One B-rep face of a CAD part: STEP entity #1117.
In plain terms, the planar face has unit normal (1, 0, 0).
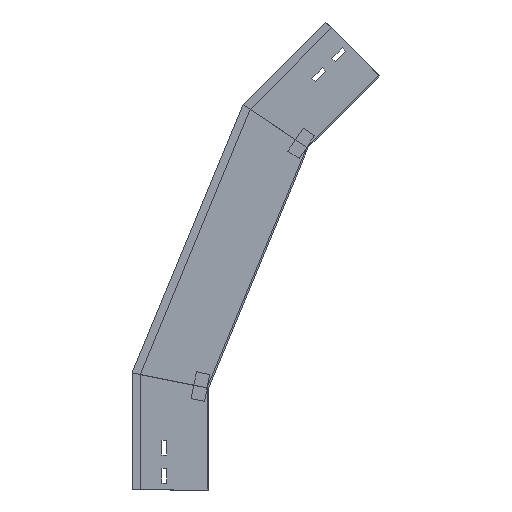
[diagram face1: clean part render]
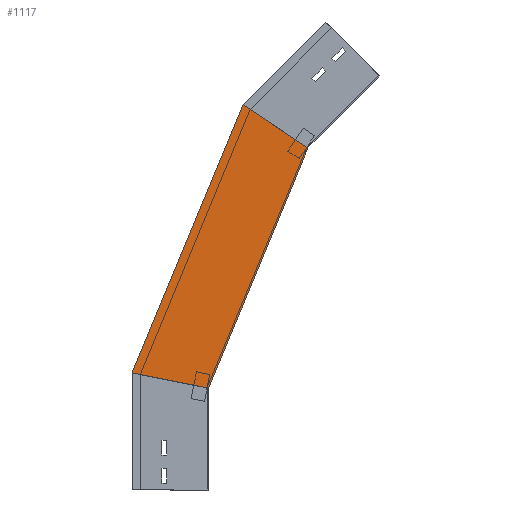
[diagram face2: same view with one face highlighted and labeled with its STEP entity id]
Its self-contained STEP definition (entity closure, numbers rounded to 3 decimals):
#14 = DIRECTION ( 'NONE',  ( 1., 0., 0. ) ) ;
#62 = VERTEX_POINT ( 'NONE', #897 ) ;
#112 = VECTOR ( 'NONE', #1214, 1000. ) ;
#138 = VERTEX_POINT ( 'NONE', #312 ) ;
#143 = CARTESIAN_POINT ( 'NONE',  ( 0., 9.458, 127.166 ) ) ;
#249 = DIRECTION ( 'NONE',  ( 0., 0., -1. ) ) ;
#297 = DIRECTION ( 'NONE',  ( 0., -0.383, 0.924 ) ) ;
#312 = CARTESIAN_POINT ( 'NONE',  ( 0., -146.568, 503.846 ) ) ;
#343 = LINE ( 'NONE', #797, #1070 ) ;
#437 = CARTESIAN_POINT ( 'NONE',  ( 0., 112.5, 172.378 ) ) ;
#478 = EDGE_CURVE ( 'NONE', #1014, #62, #1464, .T. ) ;
#521 = ORIENTED_EDGE ( 'NONE', *, *, #478, .T. ) ;
#571 = ORIENTED_EDGE ( 'NONE', *, *, #1449, .T. ) ;
#575 = CARTESIAN_POINT ( 'NONE',  ( 0., 0., 150. ) ) ;
#749 = CARTESIAN_POINT ( 'NONE',  ( 0., 113.395, 170.218 ) ) ;
#755 = LINE ( 'NONE', #1327, #112 ) ;
#761 = CARTESIAN_POINT ( 'NONE',  ( 0., -212.704, 459.655 ) ) ;
#786 = LINE ( 'NONE', #761, #1204 ) ;
#797 = CARTESIAN_POINT ( 'NONE',  ( 0., -28.701, 144.291 ) ) ;
#806 = AXIS2_PLACEMENT_3D ( 'NONE', #143, #14, #249 ) ;
#879 = EDGE_CURVE ( 'NONE', #1044, #138, #755, .T. ) ;
#897 = CARTESIAN_POINT ( 'NONE',  ( 0., -51.195, 567.572 ) ) ;
#931 = PLANE ( 'NONE',  #806 ) ;
#968 = ORIENTED_EDGE ( 'NONE', *, *, #988, .F. ) ;
#988 = EDGE_CURVE ( 'NONE', #1014, #1044, #343, .T. ) ;
#1014 = VERTEX_POINT ( 'NONE', #437 ) ;
#1044 = VERTEX_POINT ( 'NONE', #575 ) ;
#1050 = ORIENTED_EDGE ( 'NONE', *, *, #879, .F. ) ;
#1070 = VECTOR ( 'NONE', #1260, 1000. ) ;
#1117 = ADVANCED_FACE ( 'NONE', ( #1187 ), #931, .T. ) ;
#1128 = EDGE_LOOP ( 'NONE', ( #521, #571, #1050, #968 ) ) ;
#1187 = FACE_OUTER_BOUND ( 'NONE', #1128, .T. ) ;
#1204 = VECTOR ( 'NONE', #1352, 1000. ) ;
#1214 = DIRECTION ( 'NONE',  ( 0., -0.383, 0.924 ) ) ;
#1223 = VECTOR ( 'NONE', #297, 1000. ) ;
#1260 = DIRECTION ( 'NONE',  ( 0., -0.981, -0.195 ) ) ;
#1327 = CARTESIAN_POINT ( 'NONE',  ( 0., 9.458, 127.166 ) ) ;
#1352 = DIRECTION ( 'NONE',  ( 0., -0.831, -0.556 ) ) ;
#1449 = EDGE_CURVE ( 'NONE', #62, #138, #786, .T. ) ;
#1464 = LINE ( 'NONE', #749, #1223 ) ;
